VERSION 5.7 ;
  NOWIREEXTENSIONATPIN ON ;
  DIVIDERCHAR "/" ;
  BUSBITCHARS "[]" ;
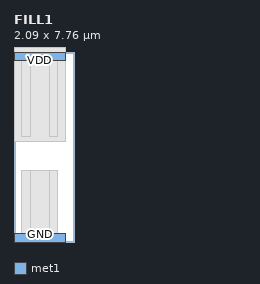
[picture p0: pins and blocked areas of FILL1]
MACRO FILL1
  CLASS CORE SPACER ;
  FOREIGN FILL1 ;
  ORIGIN 0.000 0.000 ;
  SIZE 2.090 BY 7.760 ;
  SYMMETRY X Y ;
  SITE unitrh ;
  PIN VDD
    DIRECTION INOUT ;
    USE POWER ;
    SHAPE ABUTMENT ;
    PORT
      LAYER met1 ;
        RECT 0.000 7.410 2.090 7.760 ;
    END
  END VDD
  PIN GND
    DIRECTION INOUT ;
    USE GROUND ;
    SHAPE ABUTMENT ;
    PORT
      LAYER met1 ;
        RECT 0.000 0.000 2.090 0.350 ;
    END
  END GND
  OBS
      LAYER nwell ;
        RECT 0.000 4.110 2.090 7.940 ;
      LAYER pwell ;
        RECT 0.320 0.350 1.770 2.900 ;
        RECT 0.000 0.000 2.090 0.350 ;
      LAYER li1 ;
        RECT 0.000 7.410 2.090 7.760 ;
        RECT 0.320 4.290 0.660 7.410 ;
        RECT 1.430 4.290 1.770 7.410 ;
        RECT 0.320 0.350 0.660 2.900 ;
        RECT 1.430 0.350 1.770 2.900 ;
        RECT 0.000 0.000 2.090 0.350 ;
  END
END FILL1
END LIBRARY

